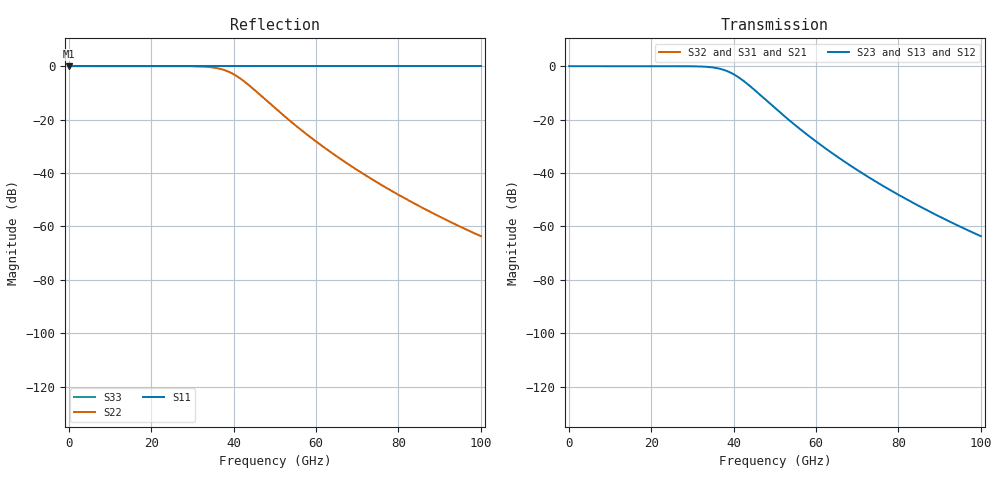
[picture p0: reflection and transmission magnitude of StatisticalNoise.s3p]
! File created by SignalIntegrity v1.5.1: Signal and Power Integrity Tools
! https://github.com/Nubis-Communications/SignalIntegrity
# MHz S MA R 50.0
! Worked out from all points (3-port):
!   1000 points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, 100 MHz to 100 GHz, reference 50 ohm
!   strongest paths, dB at 100 MHz, 25.1 GHz, 50.1 GHz, 75.1 GHz, 100 GHz:
!     S23: 0.0, 0.0, -15.8, -43.8, -63.7
!     S13: 0.0, 0.0, -15.8, -43.8, -63.7
!     S12: 0.0, 0.0, -15.8, -43.8, -63.7
!     S32: -, -, -, -, -
!     S31: -, -, -, -, -
!     S21: -, -, -, -, -
!   lowest |S11| = 0.0 dB at 100 MHz (marker M1)
!   |S11| at or under -10 dB: nowhere
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100  1 0.0  1 -0.7  1 -0.7
     0 0.0  1 -0.7  1 -0.7
     0 0.0  0 0.0  0 0.0
11900  1 0.0  1 -88.3  1 -88.3
       0 0.0  1 -88.3  1 -88.3
       0 0.0  0 0.0  0 0.0
16900  1 0.0  1 -126.9  1 -126.9
       0 0.0  1 -126.9  1 -126.9
       0 0.0  0 0.0  0 0.0
22500  1 0.0  1 -172.3  1 -172.3
       0 0.0  1 -172.3  1 -172.3
       0 0.0  0 0.0  0 0.0
27100  1 0.0  0.999 147.5  0.999 147.5
       0 0.0  0.999 147.5  0.999 147.5
       0 0.0  0 0.0  0 0.0
31800  1 0.0  0.9875 101.3  0.9875 101.3
       0 0.0  0.9875 101.3  0.9875 101.3
       0 0.0  0 0.0  0 0.0
38100  1 0.0  0.8279 25.2  0.8279 25.2
       0 0.0  0.8279 25.2  0.8279 25.2
       0 0.0  0 0.0  0 0.0
42800  1 0.0  0.503 -34.7  0.503 -34.7
       0 0.0  0.503 -34.7  0.503 -34.7
       0 0.0  0 0.0  0 0.0
50100  1 0.0  0.1629 -99.9  0.1629 -99.9
       0 0.0  0.1629 -99.9  0.1629 -99.9
       0 0.0  0 0.0  0 0.0
100000  1 0.0  0.000655 119.8  0.000655 119.8
        0 0.0  0.000655 119.8  0.000655 119.8
        0 0.0  0 0.0  0 0.0
